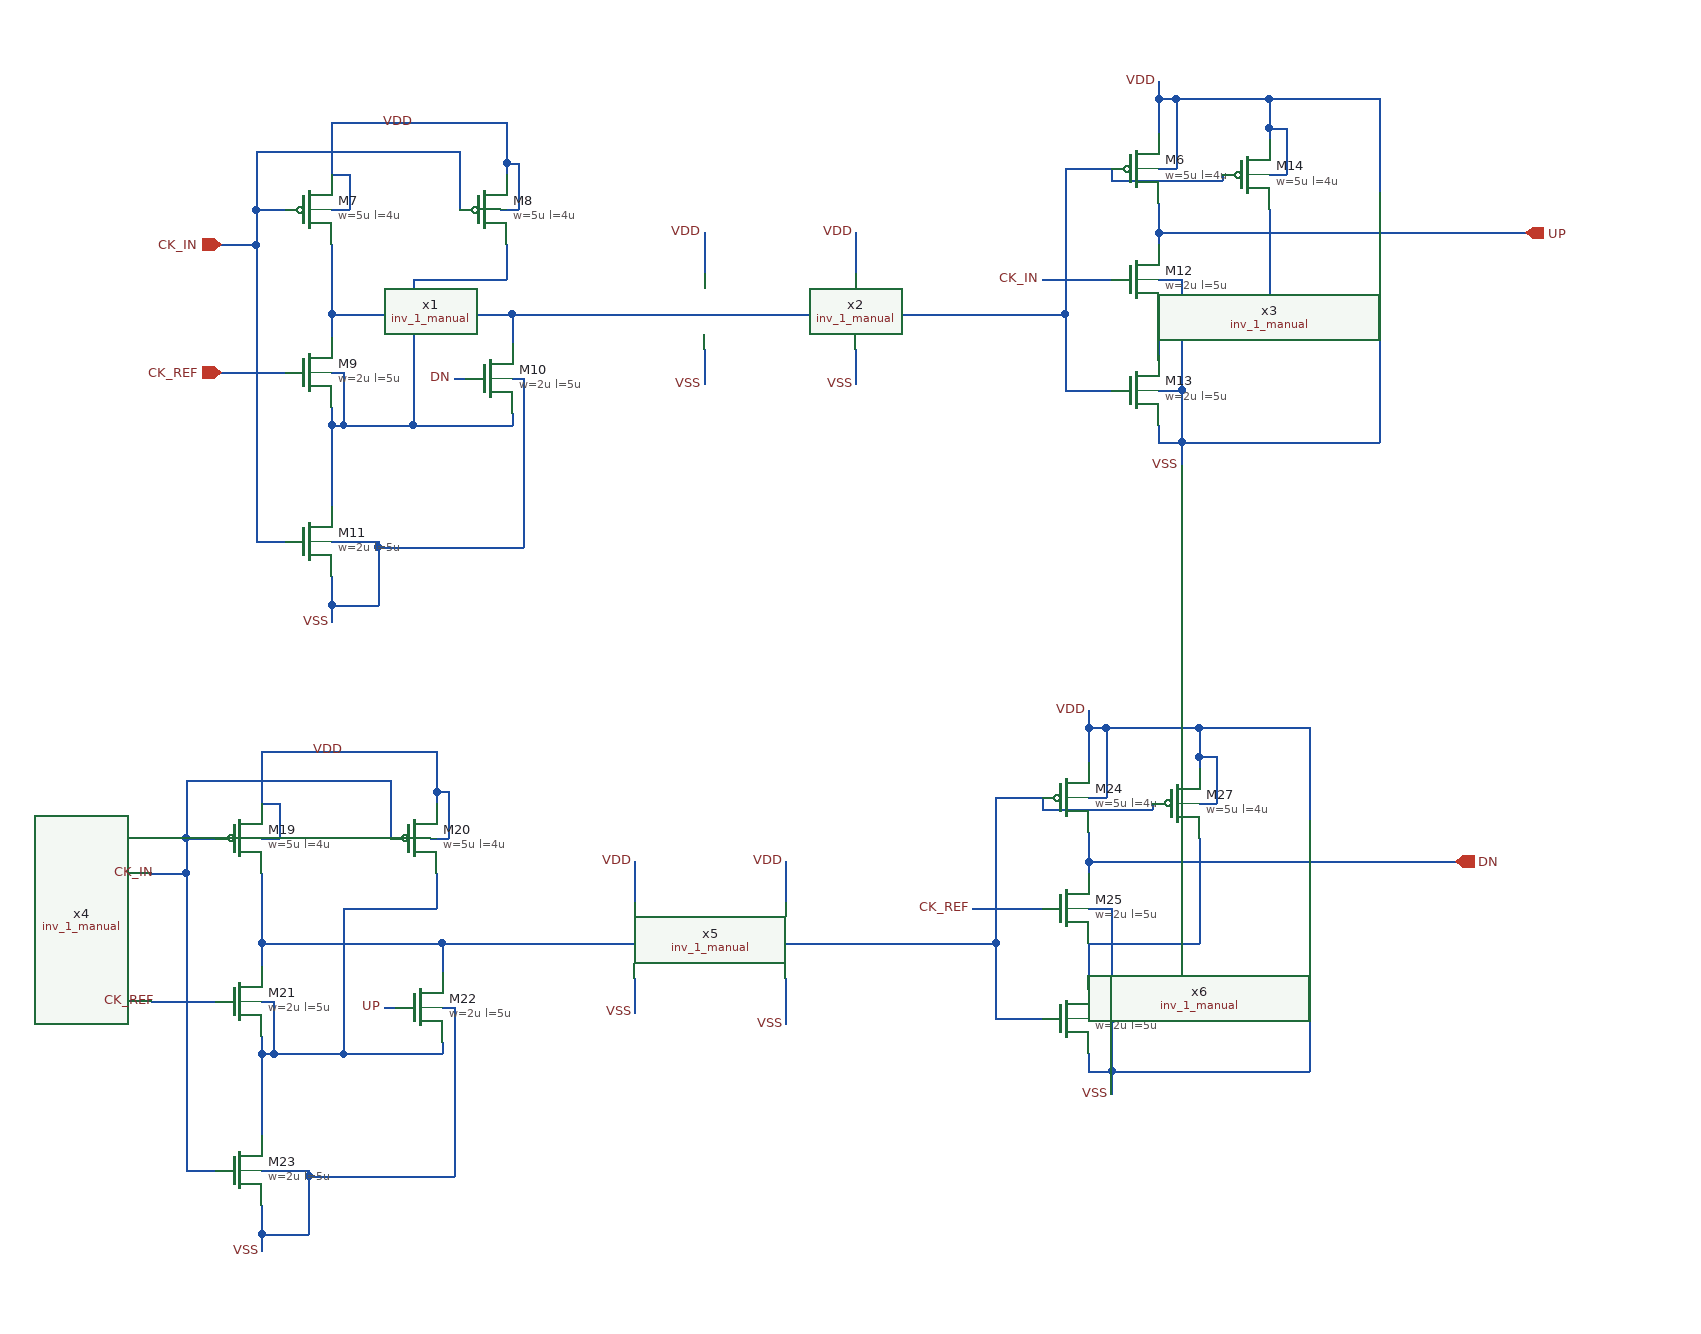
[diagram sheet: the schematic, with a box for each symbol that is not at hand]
v {xschem version=3.4.8RC file_version=1.2}
G {}
K {}
V {}
S {}
F {}
E {}
N 540 85 540 155 {lab=#net1}
N 695 75 695 85 {lab=#net1}
N 540 70 540 85 {lab=#net1}
N 540 -10 540 10 {lab=#net2}
N 540 -70 540 -10 {lab=#net2}
N 695 -10 695 15 {lab=#net2}
N 540 -10 695 -10 {lab=#net2}
N 540 240 540 255 {lab=VSS}
N 475 185 500 185 {lab=CK_IN}
N 475 -70 475 185 {lab=CK_IN}
N 475 -100 500 -100 {lab=CK_IN}
N 445 40 500 40 {lab=CK_REF}
N 445 -70 475 -70 {lab=CK_IN}
N 475 -100 475 -70 {lab=CK_IN}
N 690 -70 690 -40 {lab=#net1}
N 610 85 695 85 {lab=#net1}
N 540 185 580 185 {lab=VSS}
N 580 190 580 240 {lab=VSS}
N 540 240 580 240 {lab=VSS}
N 540 215 540 240 {lab=VSS}
N 540 -175 540 -130 {lab=VDD}
N 540 -175 690 -175 {lab=VDD}
N 475 -150 475 -100 {lab=CK_IN}
N 475 -150 650 -150 {lab=CK_IN}
N 650 -150 650 -100 {lab=CK_IN}
N 690 -140 690 -130 {lab=VDD}
N 695 45 705 45 {lab=VSS}
N 705 45 705 190 {lab=VSS}
N 580 190 705 190 {lab=VSS}
N 580 185 580 190 {lab=VSS}
N 990 -80 990 -45 {lab=VDD}
N 860 -80 860 -45 {lab=VDD}
N 1250 -135 1265 -135 {lab=VDD}
N 1210 -135 1210 -125 {lab=#net2}
N 1210 -125 1305 -125 {lab=#net2}
N 1305 -130 1305 -125 {lab=#net2}
N 1250 -195 1250 -165 {lab=VDD}
N 1265 -195 1345 -195 {lab=VDD}
N 1345 -170 1345 -160 {lab=VDD}
N 1265 -195 1265 -135 {lab=VDD}
N 1250 -195 1265 -195 {lab=VDD}
N 1250 -80 1250 -70 {lab=UP}
N 1250 -10 1250 30 {lab=#net3}
N 1250 55 1270 55 {lab=#net4}
N 1270 55 1270 100 {lab=#net4}
N 1250 85 1250 100 {lab=#net4}
N 1170 -135 1210 -135 {lab=#net2}
N 1170 -10 1170 55 {lab=#net2}
N 1170 55 1210 55 {lab=#net2}
N 1170 -135 1170 -10 {lab=#net2}
N 1250 -80 1565 -80 {lab=UP}
N 1250 -105 1250 -80 {lab=UP}
N 1250 -40 1270 -40 {lab=#net4}
N 1270 -40 1270 55 {lab=#net4}
N 1250 -210 1250 -195 {lab=VDD}
N 1250 100 1270 100 {lab=#net4}
N 1440 -195 1440 -115 {lab=VDD}
N 1345 -195 1440 -195 {lab=VDD}
N 1440 -45 1440 100 {lab=#net4}
N 1270 100 1440 100 {lab=#net4}
N 1150 -40 1210 -40 {lab=CK_IN}
N 540 -100 555 -100 {lab=VDD}
N 540 -130 555 -130 {lab=VDD}
N 555 -130 555 -100 {lab=VDD}
N 550 85 610 85 {lab=#net1}
N 610 -40 690 -40 {lab=#net1}
N 610 -40 610 85 {lab=#net1}
N 1250 -10 1345 -10 {lab=#net3}
N 1345 -100 1345 -10 {lab=#net3}
N 645 45 655 45 {lab=DN}
N 1345 -130 1360 -130 {lab=VDD}
N 1360 -170 1360 -130 {lab=VDD}
N 1345 -170 1360 -170 {lab=VDD}
N 1345 -195 1345 -170 {lab=VDD}
N 540 40 550 40 {lab=#net1}
N 550 40 550 85 {lab=#net1}
N 540 85 550 85 {lab=#net1}
N 685 -100 700 -100 {lab=VDD}
N 700 -140 700 -100 {lab=VDD}
N 690 -140 700 -140 {lab=VDD}
N 690 -175 690 -140 {lab=VDD}
N 1270 100 1270 120 {lab=#net4}
N 480 625 480 695 {lab=#net5}
N 635 615 635 625 {lab=#net5}
N 480 610 480 625 {lab=#net5}
N 480 530 480 550 {lab=#net6}
N 480 470 480 530 {lab=#net6}
N 635 530 635 555 {lab=#net6}
N 480 530 635 530 {lab=#net6}
N 480 780 480 795 {lab=VSS}
N 415 725 440 725 {lab=CK_IN}
N 415 470 415 725 {lab=CK_IN}
N 415 440 440 440 {lab=CK_IN}
N 385 580 440 580 {lab=CK_REF}
N 385 470 415 470 {lab=CK_IN}
N 415 440 415 470 {lab=CK_IN}
N 630 470 630 500 {lab=#net5}
N 550 625 635 625 {lab=#net5}
N 480 725 520 725 {lab=VSS}
N 520 730 520 780 {lab=VSS}
N 480 780 520 780 {lab=VSS}
N 480 755 480 780 {lab=VSS}
N 480 365 480 410 {lab=VDD}
N 480 365 630 365 {lab=VDD}
N 415 390 415 440 {lab=CK_IN}
N 415 390 590 390 {lab=CK_IN}
N 590 390 590 440 {lab=CK_IN}
N 630 400 630 410 {lab=VDD}
N 635 585 645 585 {lab=VSS}
N 645 585 645 730 {lab=VSS}
N 520 730 645 730 {lab=VSS}
N 520 725 520 730 {lab=VSS}
N 930 460 930 495 {lab=VDD}
N 800 460 800 495 {lab=VDD}
N 1190 405 1205 405 {lab=VDD}
N 1150 405 1150 415 {lab=#net6}
N 1150 415 1245 415 {lab=#net6}
N 1245 410 1245 415 {lab=#net6}
N 1190 345 1190 375 {lab=VDD}
N 1205 345 1285 345 {lab=VDD}
N 1285 370 1285 380 {lab=VDD}
N 1205 345 1205 405 {lab=VDD}
N 1190 345 1205 345 {lab=VDD}
N 1190 460 1190 470 {lab=DN}
N 1190 530 1190 570 {lab=#net7}
N 1190 595 1210 595 {lab=#net8}
N 1210 595 1210 640 {lab=#net8}
N 1190 625 1190 640 {lab=#net8}
N 1110 405 1150 405 {lab=#net6}
N 1110 530 1110 595 {lab=#net6}
N 1110 595 1150 595 {lab=#net6}
N 1110 405 1110 530 {lab=#net6}
N 1190 460 1505 460 {lab=DN}
N 1190 435 1190 460 {lab=DN}
N 1190 500 1210 500 {lab=#net8}
N 1210 500 1210 595 {lab=#net8}
N 1190 330 1190 345 {lab=VDD}
N 1190 640 1210 640 {lab=#net8}
N 1380 345 1380 425 {lab=VDD}
N 1285 345 1380 345 {lab=VDD}
N 1380 495 1380 640 {lab=#net8}
N 1210 640 1380 640 {lab=#net8}
N 1090 500 1150 500 {lab=CK_REF}
N 480 440 495 440 {lab=VDD}
N 480 410 495 410 {lab=VDD}
N 495 410 495 440 {lab=VDD}
N 490 625 550 625 {lab=#net5}
N 550 500 630 500 {lab=#net5}
N 550 500 550 625 {lab=#net5}
N 1190 530 1285 530 {lab=#net7}
N 1285 440 1285 530 {lab=#net7}
N 585 585 595 585 {lab=UP}
N 1285 410 1300 410 {lab=VDD}
N 1300 370 1300 410 {lab=VDD}
N 1285 370 1300 370 {lab=VDD}
N 1285 345 1285 370 {lab=VDD}
N 480 580 490 580 {lab=#net5}
N 490 580 490 625 {lab=#net5}
N 480 625 490 625 {lab=#net5}
N 625 440 640 440 {lab=VDD}
N 640 400 640 440 {lab=VDD}
N 630 400 640 400 {lab=VDD}
N 630 365 630 400 {lab=VDD}
N 1210 640 1210 660 {lab=#net8}
N 990 20 990 50 {lab=VSS}
N 860 20 860 50 {lab=VSS}
N 800 560 800 590 {lab=VSS}
N 930 560 930 600 {lab=VSS}
N 695 -10 1170 -10 {lab=#net2}
N 635 530 1110 530 {lab=#net6}
C {opin.sym} 1565 -80 0 0 {name=p3 lab=UP}
C {sg13g2_pr/sg13_lv_pmos.sym} 520 -100 0 0 {name=M7
l=4u
w=5u
ng=1
m=1
model=sg13_lv_pmos
spiceprefix=X
}
C {sg13g2_pr/sg13_lv_pmos.sym} 670 -100 0 0 {name=M8
l=4u
w=5u
ng=1
m=1
model=sg13_lv_pmos
spiceprefix=X
}
C {sg13g2_pr/sg13_lv_nmos.sym} 520 40 0 0 {name=M9
l=5u
w=2u
ng=5
m=1
model=sg13_lv_nmos
spiceprefix=X
}
C {sg13g2_pr/sg13_lv_nmos.sym} 675 45 0 0 {name=M10
l=5u
w=2u
ng=5
m=1
model=sg13_lv_nmos
spiceprefix=X
}
C {sg13g2_pr/sg13_lv_nmos.sym} 520 185 0 0 {name=M11
l=5u
w=2u
ng=5
m=1
model=sg13_lv_nmos
spiceprefix=X
}
C {devices/ipin.sym} 445 -70 0 0 {name=p6 lab=CK_IN
}
C {devices/ipin.sym} 445 40 0 0 {name=p7 lab=CK_REF
}
C {sg13g2_pr/sg13_lv_pmos.sym} 1230 -135 0 0 {name=M6
l=4u
w=5u
ng=1
m=1
model=sg13_lv_pmos
spiceprefix=X
}
C {sg13g2_pr/sg13_lv_nmos.sym} 1230 -40 0 0 {name=M12
l=5u
w=2u
ng=5
m=1
model=sg13_lv_nmos
spiceprefix=X
}
C {sg13g2_pr/sg13_lv_nmos.sym} 1230 55 0 0 {name=M13
l=5u
w=2u
ng=5
m=1
model=sg13_lv_nmos
spiceprefix=X
}
C {sg13g2_pr/sg13_lv_pmos.sym} 1325 -130 0 0 {name=M14
l=4u
w=5u
ng=1
m=1
model=sg13_lv_pmos
spiceprefix=X
}
C {lab_pin.sym} 645 45 0 0 {name=p5 sig_type=std_logic lab=DN}
C {lab_pin.sym} 1150 -40 0 0 {name=p19 sig_type=std_logic lab=CK_IN}
C {devices/lab_pin.sym} 540 255 3 0 {name=p9 sig_type=std_logic lab=VSS}
C {devices/lab_pin.sym} 1269.29538243495 120 3 0 {name=p18 sig_type=std_logic lab=VSS}
C {devices/lab_pin.sym} 612.5 -175 1 0 {name=p22 sig_type=std_logic lab=VDD}
C {devices/lab_pin.sym} 860 -80 1 0 {name=p21 sig_type=std_logic lab=VDD}
C {devices/lab_pin.sym} 990 -80 1 0 {name=p23 sig_type=std_logic lab=VDD}
C {devices/lab_pin.sym} 1250 -210 1 0 {name=p28 sig_type=std_logic lab=VDD}
C {/foss/designs/UNIC-CASS-Aug25/sch/inv_1_manual/inv_1_manual.sym} 860 -130 0 0 {name=x1
spice_ignore=true}
C {/foss/designs/UNIC-CASS-Aug25/sch/inv_1_manual/inv_1_manual.sym} 990 -130 0 0 {name=x2
spice_ignore=true}
C {/foss/designs/UNIC-CASS-Aug25/sch/inv_1_manual/inv_1_manual.sym} 1440 -200 0 0 {name=x3
spice_ignore=true}
C {opin.sym} 1505 460 0 0 {name=p1 lab=DN}
C {sg13g2_pr/sg13_lv_pmos.sym} 460 440 0 0 {name=M19
l=4u
w=5u
ng=1
m=1
model=sg13_lv_pmos
spiceprefix=X
}
C {sg13g2_pr/sg13_lv_pmos.sym} 610 440 0 0 {name=M20
l=4u
w=5u
ng=1
m=1
model=sg13_lv_pmos
spiceprefix=X
}
C {sg13g2_pr/sg13_lv_nmos.sym} 460 580 0 0 {name=M21
l=5u
w=2u
ng=5
m=1
model=sg13_lv_nmos
spiceprefix=X
}
C {sg13g2_pr/sg13_lv_nmos.sym} 615 585 0 0 {name=M22
l=5u
w=2u
ng=5
m=1
model=sg13_lv_nmos
spiceprefix=X
}
C {sg13g2_pr/sg13_lv_nmos.sym} 460 725 0 0 {name=M23
l=5u
w=2u
ng=5
m=1
model=sg13_lv_nmos
spiceprefix=X
}
C {sg13g2_pr/sg13_lv_pmos.sym} 1170 405 0 0 {name=M24
l=4u
w=5u
ng=1
m=1
model=sg13_lv_pmos
spiceprefix=X
}
C {sg13g2_pr/sg13_lv_nmos.sym} 1170 500 0 0 {name=M25
l=5u
w=2u
ng=5
m=1
model=sg13_lv_nmos
spiceprefix=X
}
C {sg13g2_pr/sg13_lv_nmos.sym} 1170 595 0 0 {name=M26
l=5u
w=2u
ng=5
m=1
model=sg13_lv_nmos
spiceprefix=X
}
C {sg13g2_pr/sg13_lv_pmos.sym} 1265 410 0 0 {name=M27
l=4u
w=5u
ng=1
m=1
model=sg13_lv_pmos
spiceprefix=X
}
C {lab_pin.sym} 585 585 0 0 {name=p17 sig_type=std_logic lab=UP}
C {lab_pin.sym} 1090 500 0 0 {name=p20 sig_type=std_logic lab=CK_REF}
C {devices/lab_pin.sym} 480 795 3 0 {name=p25 sig_type=std_logic lab=VSS}
C {devices/lab_pin.sym} 1209.29538243495 660 3 0 {name=p35 sig_type=std_logic lab=VSS}
C {devices/lab_pin.sym} 552.5 365 1 0 {name=p36 sig_type=std_logic lab=VDD}
C {devices/lab_pin.sym} 800 460 1 0 {name=p37 sig_type=std_logic lab=VDD}
C {devices/lab_pin.sym} 930 460 1 0 {name=p38 sig_type=std_logic lab=VDD}
C {devices/lab_pin.sym} 1190 330 1 0 {name=p39 sig_type=std_logic lab=VDD}
C {/foss/designs/UNIC-CASS-Aug25/sch/inv_1_manual/inv_1_manual.sym} 850 270 0 0 {name=x4
spice_ignore=true}
C {/foss/designs/UNIC-CASS-Aug25/sch/inv_1_manual/inv_1_manual.sym} 930 410 0 0 {name=x5
spice_ignore=true}
C {/foss/designs/UNIC-CASS-Aug25/sch/inv_1_manual/inv_1_manual.sym} 1380 340 0 0 {name=x6
spice_ignore=true}
C {lab_pin.sym} 390 470 0 0 {name=p2 sig_type=std_logic lab=CK_IN}
C {lab_pin.sym} 390 580 0 0 {name=p4 sig_type=std_logic lab=CK_REF}
C {lab_pin.sym} 860 50 3 0 {name=p8 sig_type=std_logic lab=VSS}
C {lab_pin.sym} 990 50 3 0 {name=p10 sig_type=std_logic lab=VSS}
C {lab_pin.sym} 800 590 3 0 {name=p11 sig_type=std_logic lab=VSS}
C {lab_pin.sym} 930 600 3 0 {name=p12 sig_type=std_logic lab=VSS}
